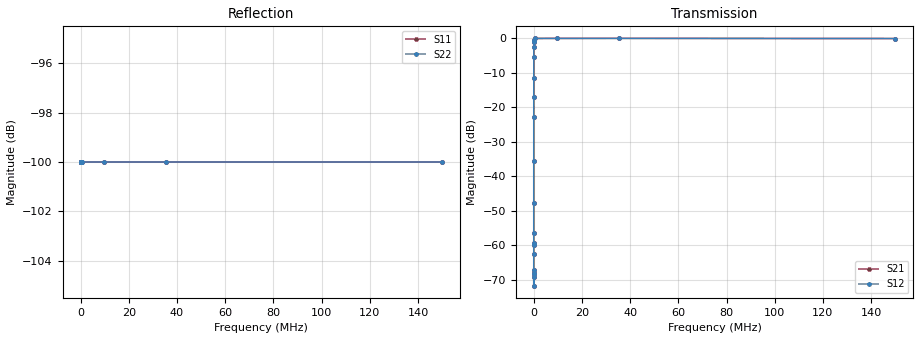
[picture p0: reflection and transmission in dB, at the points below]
! 7/27/2020 12:23 PM
! H:\MS4647B\Production_Data\9437-11\Juan_5\Juan_5_LF_2020-07-27_11-51-04_s2p.s2p
! CORRECTED DATA
# Hz S DB R 50.0
! FREQ  S11DB  S11A  S21DB  S21A  S12DB  S12A  S22DB  S22A
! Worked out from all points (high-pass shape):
!   401 points, 10 Hz to 150 MHz, reference 50 ohm
!   highest |S21| = -0.05 dB at 35.33 MHz (marker M1); lowest = -71.7 dB at 12.29 Hz (marker M2)
!   |S21| within 3 dB of the highest: 35.18 kHz to end of sweep
!   lowest |S11| = -100.0 dB at 10 Hz (marker M3), VSWR 1.00, Z = 50 + j0 ohm
!   |S11| at or under -10 dB: start of sweep to end of sweep
!   |S22| runs from -100.0 to -100.0 dB; largest |S21 - S12| = 0
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10  -100.00 0.0  -69.16 -69.2  -69.16 -69.2  -100.00 0.0
12.29423  -100.00 0.0  -71.69 -71.7  -71.69 -71.7  -100.00 0.0
14.50314  -100.00 0.0  -68.15 -68.2  -68.15 -68.2  -100.00 0.0
17.83049  -100.00 0.0  -68.33 -68.3  -68.33 -68.3  -100.00 0.0
20.18291  -100.00 0.0  -67.10 -67.1  -67.10 -67.1  -100.00 0.0
34.53082  -100.00 0.0  -62.50 -62.5  -62.50 -62.5  -100.00 0.0
42.45296  -100.00 0.0  -59.76 -59.8  -59.76 -59.8  -100.00 0.0
48.0539  -100.00 0.0  -59.43 -59.4  -59.43 -59.4  -100.00 0.0
59.07855  -100.00 0.0  -56.55 -56.6  -56.55 -56.6  -100.00 0.0
159.2191  -100.00 0.0  -47.87 -47.9  -47.87 -47.9  -100.00 0.0
597.1488  -100.00 0.0  -35.46 -35.5  -35.46 -35.5  -100.00 0.0
2535.074  -100.00 0.0  -22.93 -22.9  -22.93 -22.9  -100.00 0.0
5116.517  -100.00 0.0  -16.96 -17.0  -16.96 -17.0  -100.00 0.0
9908.732  -100.00 0.0  -11.41 -11.4  -11.41 -11.4  -100.00 0.0
22637.2  -100.00 0.0  -5.36 -5.4  -5.36 -5.4  -100.00 0.0
40363.22  -100.00 0.0  -2.51 -2.5  -2.51 -2.5  -100.00 0.0
63581.15  -100.00 0.0  -1.20 -1.2  -1.20 -1.2  -100.00 0.0
108780.6  -100.00 0.0  -0.49 -0.5  -0.49 -0.5  -100.00 0.0
616653.1  -100.00 0.0  -0.07 -0.1  -0.07 -0.1  -100.00 0.0
9818298  -100.00 0.0  -0.06 -0.1  -0.06 -0.1  -100.00 0.0
3.533322e7  -100.00 0.0  -0.05 -0.1  -0.05 -0.1  -100.00 0.0
1.5e8  -100.00 0.0  -0.10 -0.1  -0.10 -0.1  -100.00 0.0
